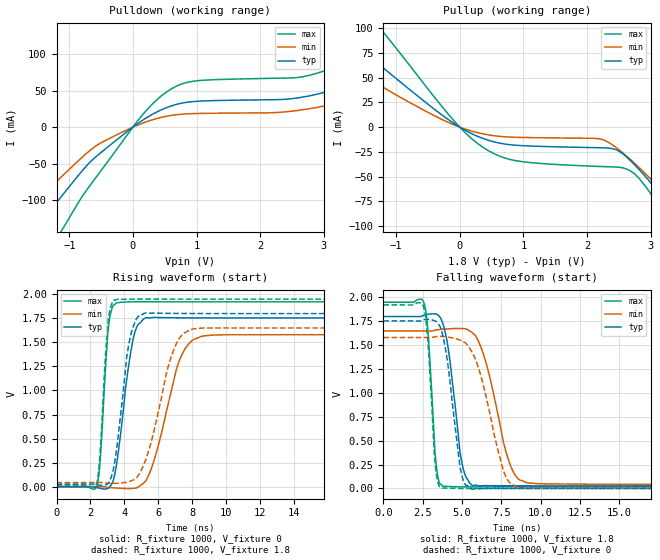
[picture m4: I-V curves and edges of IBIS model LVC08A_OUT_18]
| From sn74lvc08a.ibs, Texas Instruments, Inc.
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[Model]   LVC08A_OUT_18
Model_type  Output
Vref =   0
Rref =   1000
Cref =   30p
Vmeas =   0.9
| variable   typ   min   max
C_comp   7.99pF   4.13pF   13.47pF
| C_pullup   7.12pF   4.13pF   8.74pF
| C_pulldown   8.87pF   4.63pF   13.47pF
[Temperature Range]   40   100   -40
| Ambient temperature   25   85   -40
[Voltage range]   1.8   1.65   1.95
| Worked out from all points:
|   slope of the pulldown table from 0 to 0.27 V, typ, clamps not added: 17.1 ohm
|   slope of the pullup table from 0 to 0.27 V, typ, clamps not added: 29.9 ohm
|   rising waveform, R_fixture 1000, V_fixture 0: 20-80 % time 745ps typ, 1.33ns min, 384ps max; typ from 0 V to 1.75 V
|   falling waveform, R_fixture 1000, V_fixture 1.8: 20-80 % time 734ps typ, 1.33ns min, 402ps max; typ from 1.8 V to 0.027 V
|   rising waveform, R_fixture 1000, V_fixture 1.8: 20-80 % time 690ps typ, 1.31ns min, 379ps max; typ from 0.027 V to 1.8 V
|   falling waveform, R_fixture 1000, V_fixture 0: 20-80 % time 775ps typ, 1.38ns min, 398ps max; typ from 1.75 V to 0 V
[Pulldown]
| LVC08A_OUT_18
|   Voltage   I(typ)   I(min)   I(max)
-5.5V     -559.1mA   -452.2mA   -710.9mA
-2.18V    -208.5mA   -158.8mA   -285.4mA
-1.865V   -175.2mA   -131.6mA   -244.5mA
-1.48V    -133.9mA   -98.56mA   -193.1mA
-1.07V    -89.31mA   -63.76mA   -134.9mA
70mV      4.491mA    2.617mA    8.125mA
615mV     29.45mA    16.27mA    53.12mA
2.815V    43.69mA    25.92mA    72.1mA
4.325V    93.52mA    64.21mA    142.7mA
5.155V    134.5mA    96.03mA    199.6mA
6.155V    191.3mA    141.3mA    276.1mA
11V       510.2mA    405.2mA    689.3mA
[Pullup]
| LVC08A_OUT_18
|   Voltage   I(typ)   I(min)   I(max)
-5.5V     324.9mA    249.5mA    454.8mA
-2.68V    143.9mA    103mA      216.3mA
-2.015V   104.9mA    73.15mA    161.8mA
-1.32V    66.21mA    44.72mA    105.6mA
360mV     -11.3mA    -6.711mA   -20.18mA
985mV     -18.72mA   -10.42mA   -34.9mA
2.465V    -23.02mA   -20.97mA   -40.36mA
2.785V    -40.46mA   -38.76mA   -49.43mA
3.365V    -85.63mA   -77.45mA   -103.2mA
3.56V     -102.6mA   -91.66mA   -124.4mA
3.775V    -122mA     -107.8mA   -148.7mA
11V       -874.4mA   -739.7mA   -1.068A
[Ramp]
| LVC08A_OUT_18
| variable   typ   min   max
dV/dt_r   1.07/7.98E-10   0.96/1.40E-09   1.17/3.92E-10
dV/dt_f   1.08/7.69E-10   0.98/1.40E-09   1.18/4.27E-10
R_load = 1000
[Rising Waveform]
| LVC08A_OUT_18
R_fixture =   1000
C_fixture =   0
L_fixture =   0
V_fixture =   0
V_fixture_min = 0
V_fixture_max = 0
|   Time   V(typ)   V(min)   V(max)
0s        194.2pV    4.892nV    16.26pV
2.38ns    -9.183mV   778.9uV    4.948mV
2.575ns   -17.41mV   1.035mV    286.9mV
3.055ns   -16.01mV   -7.256mV   1.655V
3.545ns   242.8mV    -14.52mV   1.912V
4.495ns   1.523V     -18.22mV   1.922V
5.235ns   1.754V     56.33mV    1.922V
7.155ns   1.756V     1.271V     1.922V
8.14ns    1.754V     1.536V     1.922V
24.99ns   1.754V     1.581V     1.922V
[Falling Waveform]
| LVC08A_OUT_18
R_fixture =   1000
C_fixture =   0
L_fixture =   0
V_fixture =   1.8
V_fixture_min = 1.65
V_fixture_max = 1.95
|   Time   V(typ)   V(min)   V(max)
0s        1.8V       1.65V      1.95V
2.585ns   1.815V     1.649V     1.941V
2.855ns   1.824V     1.648V     1.597V
3.345ns   1.827V     1.658V     270mV
3.795ns   1.719V     1.668V     22.29mV
4.945ns   312.9mV    1.675V     16.19mV
5.645ns   32.59mV    1.632V     15.83mV
7.925ns   27.39mV    315.2mV    16.27mV
8.695ns   27.19mV    86.61mV    16.27mV
24.99ns   27.13mV    42.42mV    16.27mV
[Rising Waveform]
| LVC08A_OUT_18
R_fixture =   1000
C_fixture =   0
L_fixture =   0
V_fixture =   1.8
V_fixture_min = 1.65
V_fixture_max = 1.95
|   Time   V(typ)   V(min)   V(max)
0s        27.13mV    42.42mV    16.27mV
2.38ns    19.62mV    43.04mV    42.1mV
2.56ns    14.41mV    43.15mV    342.4mV
3.01ns    29.28mV    36.79mV    1.672V
3.39ns    217.8mV    34.09mV    1.941V
4.22ns    1.442V     49.66mV    1.949V
4.89ns    1.781V     138.8mV    1.95V
6.815ns   1.802V     1.38V      1.95V
7.88ns    1.8V       1.631V     1.95V
24.99ns   1.8V       1.65V      1.95V
[Falling Waveform]
| LVC08A_OUT_18
R_fixture =   1000
C_fixture =   0
L_fixture =   0
V_fixture =   0
V_fixture_min = 0
V_fixture_max = 0
|   Time   V(typ)   V(min)   V(max)
0s        1.754V     1.581V     1.922V
2.555ns   1.766V     1.581V     1.901V
2.83ns    1.771V     1.579V     1.542V
3.305ns   1.753V     1.588V     238mV
3.74ns    1.628V     1.592V     4.61mV
4.875ns   223.5mV    1.553V     -69.75uV
5.58ns    -3.421mV   1.444V     -401.4uV
7.645ns   29.43uV    179.6mV    -1.782uV
8.48ns    -4.978uV   13.11mV    2.683uV
24.99ns   11.55nV    397.2nV    23.41nV
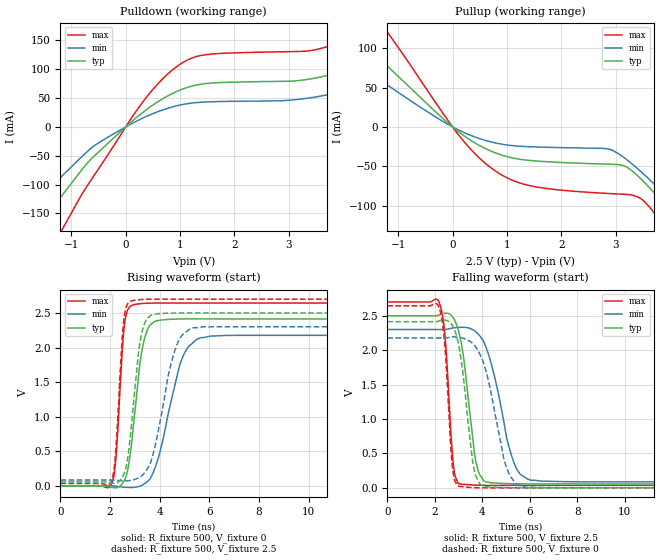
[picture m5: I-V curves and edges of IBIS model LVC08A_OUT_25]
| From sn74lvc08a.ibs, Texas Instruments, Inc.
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[Model]   LVC08A_OUT_25
Model_type  Output
Vref =   0
Rref =   500
Cref =   30p
Vmeas =   1.25
| variable   typ   min   max
C_comp   7.79pF   3.92pF   11.77pF
| C_pullup   7.19pF   3.92pF   8.82pF
| C_pulldown   8.39pF   4.37pF   11.77pF
[Temperature Range]   40   100   -40
| Ambient temperature   25   85   -40
[Voltage range]   2.5   2.3   2.7
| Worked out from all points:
|   slope of the pulldown table from 0 to 0.375 V, typ, clamps not added: 12.7 ohm
|   slope of the pullup table from 0 to 0.375 V, typ, clamps not added: 20 ohm
|   rising waveform, R_fixture 500, V_fixture 0: 20-80 % time 451ps typ, 837ps min, 261ps max; typ from 0 V to 2.41 V
|   falling waveform, R_fixture 500, V_fixture 2.5: 20-80 % time 492ps typ, 847ps min, 284ps max; typ from 2.5 V to 0.057 V
|   rising waveform, R_fixture 500, V_fixture 2.5: 20-80 % time 417ps typ, 744ps min, 254ps max; typ from 0.057 V to 2.5 V
|   falling waveform, R_fixture 500, V_fixture 0: 20-80 % time 483ps typ, 781ps min, 272ps max; typ from 2.41 V to 0 V
[Pulldown]
| LVC08A_OUT_25
|   Voltage   I(typ)   I(min)   I(max)
-5.5V     -598.1mA   -479.8mA   -766.5mA
-2.12V    -233mA     -174.4mA   -327.1mA
-1.575V   -168.1mA   -123.2mA   -244.7mA
-1.15V    -116.2mA   -83.21mA   -174.9mA
-565mV    -49.19mA   -31.72mA   -81.94mA
365mV     28.75mA    17.58mA    49.46mA
1.32V     73.05mA    42.4mA     122.5mA
4V        96.78mA    61.72mA    149.2mA
4.6V      117.3mA    77.78mA    177.9mA
5.77V     171.8mA    120.4mA    253.2mA
7.055V    245.3mA    179.5mA    351.5mA
11V       504.9mA    394.6mA    686.5mA
[Pullup]
| LVC08A_OUT_25
|   Voltage   I(typ)   I(min)   I(max)
-5.5V     363.4mA    279.9mA    508.8mA
-2.6V     169.4mA    122.6mA    251.6mA
-1.815V   117.7mA    83.03mA    179.1mA
-1.37V    88.47mA    61.37mA    136.9mA
170mV     -9.222mA   -5.867mA   -15.32mA
760mV     -32.2mA    -19.89mA   -54.58mA
2.905V    -47.35mA   -28.79mA   -84.65mA
3.45V     -65.04mA   -55.88mA   -90.57mA
3.92V     -100.7mA   -87.07mA   -129.3mA
4.19V     -123.8mA   -106.6mA   -157.6mA
4.495V    -151.4mA   -129.7mA   -191.8mA
11V       -830.2mA   -699.2mA   -1.022A
[Ramp]
| LVC08A_OUT_25
| variable   typ   min   max
dV/dt_r   1.47/4.87E-10   1.32/8.53E-10   1.60/2.70E-10
dV/dt_f   1.49/5.05E-10   1.35/9.27E-10   1.62/3.01E-10
R_load = 500
[Rising Waveform]
| LVC08A_OUT_25
R_fixture =   500
C_fixture =   0
L_fixture =   0
V_fixture =   0
V_fixture_min = 0
V_fixture_max = 0
|   Time   V(typ)   V(min)   V(max)
0s        177.7pV    3.877nV    17.91pV
2.07ns    -22.02mV   560.8uV    36.86mV
2.24ns    -27.06mV   -4.436mV   430.2mV
2.58ns    81.63mV    -19.14mV   2.332V
2.97ns    970.4mV    -21.08mV   2.621V
3.26ns    1.903V     4.014mV    2.636V
3.58ns    2.311V     88.76mV    2.642V
4.85ns    2.414V     1.79V      2.644V
5.635ns   2.415V     2.14V      2.644V
24.99ns   2.414V     2.176V     2.644V
[Falling Waveform]
| LVC08A_OUT_25
R_fixture =   500
C_fixture =   0
L_fixture =   0
V_fixture =   2.5
V_fixture_min = 2.3
V_fixture_max = 2.7
|   Time   V(typ)   V(min)   V(max)
0s        2.5V       2.3V       2.7V
2.195ns   2.515V     2.299V     2.683V
2.43ns    2.536V     2.302V     2.202V
2.78ns    2.468V     2.323V     338.9mV
3.015ns   2.256V     2.33V      59.62mV
3.7ns     434.7mV    2.275V     39.3mV
4.155ns   81.17mV    2.043V     35.68mV
5.265ns   59.85mV    433mV      35.72mV
6ns       57.06mV    114.5mV    35.91mV
24.99ns   57.33mV    84.96mV    35.94mV
[Rising Waveform]
| LVC08A_OUT_25
R_fixture =   500
C_fixture =   0
L_fixture =   0
V_fixture =   2.5
V_fixture_min = 2.3
V_fixture_max = 2.7
|   Time   V(typ)   V(min)   V(max)
0s        57.33mV    84.96mV    35.94mV
2.07ns    39.04mV    85.25mV    90.9mV
2.225ns   40.48mV    81.25mV    480.6mV
2.545ns   160.5mV    72.41mV    2.37V
2.85ns    829.6mV    80.21mV    2.674V
3.16ns    1.964V     117.3mV    2.692V
3.45ns    2.396V     218.4mV    2.698V
4.61ns    2.5V       1.954V     2.7V
5.33ns    2.501V     2.284V     2.7V
24.99ns   2.5V       2.3V       2.7V
[Falling Waveform]
| LVC08A_OUT_25
R_fixture =   500
C_fixture =   0
L_fixture =   0
V_fixture =   0
V_fixture_min = 0
V_fixture_max = 0
|   Time   V(typ)   V(min)   V(max)
0s        2.414V     2.176V     2.644V
2.175ns   2.425V     2.176V     2.623V
2.41ns    2.437V     2.178V     2.124V
2.74ns    2.358V     2.192V     312.7mV
3.05ns    1.986V     2.183V     19.38mV
3.76ns    144.7mV    2.026V     1.54mV
4.215ns   15.27mV    1.615V     -394.9uV
4.975ns   2.244mV    342.1mV    -316.2uV
5.565ns   -223.9uV   30.98mV    -77.42uV
24.99ns   22.62nV    1.88nV     9.726nV
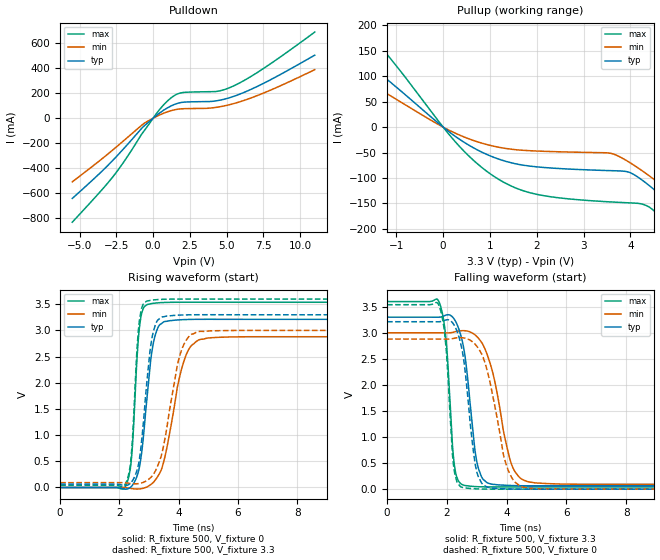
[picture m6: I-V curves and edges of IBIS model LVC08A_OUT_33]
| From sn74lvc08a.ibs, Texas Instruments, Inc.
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[Model]   LVC08A_OUT_33
Model_type  Output
Vref =   0
Rref =   500
Cref =   50p
Vmeas =   1.5
| variable   typ   min   max
C_comp   7.48pF   3.90pF   11.11pF
| C_pullup   7.16pF   3.90pF   8.83pF
| C_pulldown   7.81pF   4.17pF   11.11pF
[Temperature Range]   40   100   -40
| Ambient temperature   25   85   -40
[Voltage range]   3.3   3   3.6
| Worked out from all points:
|   slope of the pulldown table from 0 to 0.495 V, typ, clamps not added: 10.7 ohm
|   slope of the pullup table from 0 to 0.495 V, typ, clamps not added: 15.2 ohm
|   rising waveform, R_fixture 500, V_fixture 0: 20-80 % time 344ps typ, 587ps min, 210ps max; typ from 0 V to 3.21 V
|   falling waveform, R_fixture 500, V_fixture 3.3: 20-80 % time 369ps typ, 621ps min, 230ps max; typ from 3.3 V to 0.065 V
|   rising waveform, R_fixture 500, V_fixture 3.3: 20-80 % time 329ps typ, 547ps min, 205ps max; typ from 0.065 V to 3.3 V
|   falling waveform, R_fixture 500, V_fixture 0: 20-80 % time 368ps typ, 596ps min, 230ps max; typ from 3.21 V to 0 V
[Pulldown]
| LVC08A_OUT_33
|   Voltage   I(typ)   I(min)   I(max)
-5.5V     -642.1mA   -509.2mA   -832.1mA
-3.645V   -442.6mA   -340.3mA   -594.1mA
-2.71V    -333.2mA   -250.5mA   -464.6mA
-1.885V   -228.4mA   -168.1mA   -330.7mA
-620mV    -62.4mA    -41.49mA   -102.1mA
455mV     42.83mA    26.93mA    71.74mA
1.215V    98.07mA    60.46mA    162.3mA
1.91V     125.9mA    75.23mA    203.5mA
4.31V     139.6mA    87.57mA    214.6mA
5.45V     173.8mA    116.3mA    257.3mA
7.53V     280.4mA    202.4mA    399.9mA
11V       505.3mA    389mA      689.8mA
[Pullup]
| LVC08A_OUT_33
|   Voltage   I(typ)   I(min)   I(max)
-5.5V     404.4mA    310.8mA    569.2mA
-3.515V   265mA      197.3mA    383.4mA
-2.48V    190.1mA    138.3mA    280.1mA
-1.635V   127.1mA    90.28mA    191.1mA
505mV     -33.05mA   -21.44mA   -52.79mA
1.855V    -76.61mA   -46.34mA   -128.9mA
3.7V      -85.85mA   -55.1mA    -147.6mA
4.24V     -103.3mA   -84.95mA   -151mA
4.895V    -154.7mA   -130.6mA   -201.2mA
5.365V    -197.4mA   -166.8mA   -253mA
5.825V    -241.6mA   -203.9mA   -307.6mA
11V       -786.6mA   -661.2mA   -974mA
[Ramp]
| LVC08A_OUT_33
| variable   typ   min   max
dV/dt_r   1.95/3.64E-10   1.75/6.33E-10   2.14/2.15E-10
dV/dt_f   1.97/3.84E-10   1.77/6.64E-10   2.16/2.42E-10
R_load = 500
[Rising Waveform]
| LVC08A_OUT_33
R_fixture =   500
C_fixture =   0
L_fixture =   0
V_fixture =   0
V_fixture_min = 0
V_fixture_max = 0
|   Time   V(typ)   V(min)   V(max)
0s        184.9pV    3.596nV    21.02pV
2.225ns   -32.07mV   -4.397mV   46.5mV
2.415ns   27.66mV    -20.48mV   616.5mV
2.68ns    405.6mV    -26.73mV   3.08V
2.955ns   1.854V     18.43mV    3.499V
3.125ns   2.698V     87.24mV    3.517V
3.345ns   3.1V       261mV      3.53V
4.155ns   3.207V     2.377V     3.539V
4.74ns    3.213V     2.831V     3.54V
24.99ns   3.212V     2.88V      3.539V
[Falling Waveform]
| LVC08A_OUT_33
R_fixture =   500
C_fixture =   0
L_fixture =   0
V_fixture =   3.3
V_fixture_min = 3
V_fixture_max = 3.6
|   Time   V(typ)   V(min)   V(max)
0s        3.3V       3V         3.6V
1.75ns    3.3V       3V         3.579V
1.98ns    3.34V      2.998V     2.834V
2.25ns    3.26V      3.016V     474.5mV
2.565ns   2.705V     3.041V     75.85mV
2.935ns   767.9mV    2.964V     49.87mV
3.16ns    237.8mV    2.818V     44.58mV
4.14ns    69.68mV    515.7mV    41.75mV
4.72ns    64.09mV    140.8mV    41.89mV
24.99ns   64.52mV    92.1mV     41.93mV
[Rising Waveform]
| LVC08A_OUT_33
R_fixture =   500
C_fixture =   0
L_fixture =   0
V_fixture =   3.3
V_fixture_min = 3
V_fixture_max = 3.6
|   Time   V(typ)   V(min)   V(max)
0s        64.52mV    92.1mV     41.93mV
2.22ns    37.55mV    88.01mV    88.73mV
2.4ns     99.27mV    75.04mV    617.1mV
2.67ns    526.3mV    77.01mV    3.165V
2.945ns   2.124V     138.3mV    3.566V
3.1ns     2.859V     216.6mV    3.579V
3.29ns    3.196V     410.9mV    3.591V
4.05ns    3.294V     2.545V     3.6V
4.67ns    3.301V     2.979V     3.6V
24.99ns   3.3V       3V         3.6V
[Falling Waveform]
| LVC08A_OUT_33
R_fixture =   500
C_fixture =   0
L_fixture =   0
V_fixture =   0
V_fixture_min = 0
V_fixture_max = 0
|   Time   V(typ)   V(min)   V(max)
0s        3.212V     2.88V      3.539V
1.74ns    3.212V     2.879V     3.519V
1.965ns   3.246V     2.878V     2.766V
2.235ns   3.157V     2.893V     407.7mV
2.54ns    2.571V     2.903V     29.79mV
3.06ns    229.3mV    2.695V     3.534mV
3.4ns     30.98mV    2.16V      44.24uV
3.99ns    5.262mV    463.4mV    -435.5uV
4.56ns    -491.2uV   34.85mV    -128.9uV
24.99ns   7.314nV    22.34nV    14.37nV
